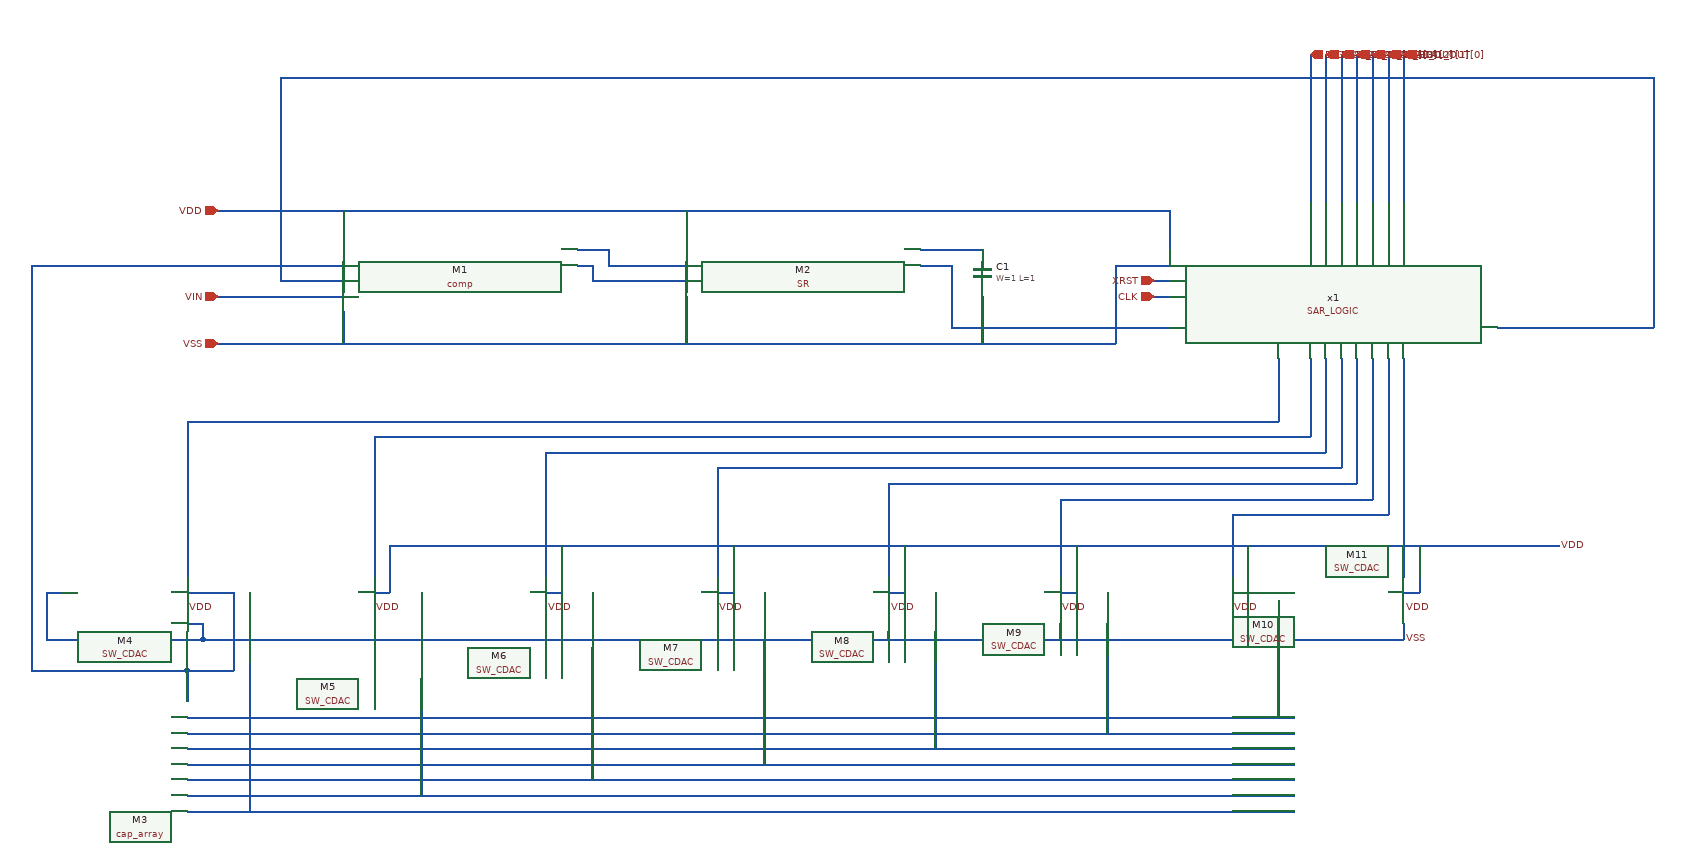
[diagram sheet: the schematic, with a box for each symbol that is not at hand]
v {xschem version=3.4.8RC file_version=1.3}
G {}
K {}
V {}
S {}
F {}
E {}
N 2480 -820 2760 -820 {
lab=#net1}
N 2740 -860 2760 -860 {
lab=CLK}
N 2740 -880 2760 -880 {
lab=XRST}
N 3060 -780 3060 -690 {
lab=#net2}
N 3040 -780 3040 -690 {
lab=#net3}
N 3020 -780 3020 -690 {
lab=#net4}
N 3000 -780 3000 -690 {
lab=#net5}
N 2980 -780 2980 -690 {
lab=#net6}
N 2960 -780 2960 -690 {
lab=#net7}
N 2940 -780 2940 -690 {
lab=#net8}
N 2900 -780 2900 -700 {
lab=#net9}
N 3180 -820 3380 -820 {
lab=#net10}
N 2000 -920 2040 -920 {
lab=#net11}
N 2000 -900 2020 -900 {
lab=#net12}
N 1500 -320 2920 -320 {
lab=#net13}
N 1500 -300 2920 -300 {
lab=#net14}
N 1500 -280 2920 -280 {
lab=#net15}
N 1500 -260 2920 -260 {
lab=#net16}
N 1500 -240 2920 -240 {
lab=#net17}
N 1500 -220 2920 -220 {
lab=#net18}
N 1500 -200 2920 -200 {
lab=#net19}
N 1740 -680 2940 -680 {
lab=#net8}
N 1740 -680 1740 -500 {
lab=#net8}
N 1960 -660 1960 -500 {
lab=#net7}
N 1960 -660 2960 -660 {
lab=#net7}
N 2180 -640 2980 -640 {
lab=#net6}
N 2180 -640 2180 -500 {
lab=#net6}
N 2400 -620 2400 -500 {
lab=#net5}
N 2400 -620 3000 -620 {
lab=#net5}
N 2620 -600 3020 -600 {
lab=#net4}
N 2620 -600 2620 -500 {
lab=#net4}
N 2840 -580 2840 -500 {
lab=#net3}
N 3060 -690 3060 -500 {
lab=#net2}
N 1500 -700 2900 -700 {
lab=#net9}
N 1500 -700 1500 -500 {
lab=#net9}
N 1320 -480 1340 -480 {
lab=VSS}
N 1320 -480 1320 -420 {
lab=VSS}
N 1320 -420 1520 -420 {
lab=VSS}
N 1520 -440 1520 -420 {
lab=VSS}
N 1500 -440 1520 -440 {
lab=VSS}
N 1500 -380 1500 -340 {
lab=#net20}
N 1300 -380 1500 -380 {
lab=#net20}
N 1300 -900 1300 -380 {
lab=#net20}
N 1300 -900 1700 -900 {
lab=#net20}
N 1500 -480 1560 -480 {
lab=#net20}
N 1560 -480 1560 -380 {
lab=#net20}
N 1500 -380 1560 -380 {
lab=#net20}
N 2840 -580 3040 -580 {
lab=#net3}
N 1620 -880 1700 -880 {
lab=#net10}
N 1620 -1140 1620 -880 {
lab=#net10}
N 1620 -1140 3380 -1140 {
lab=#net10}
N 3380 -1140 3380 -820 {
lab=#net10}
N 2440 -900 2480 -900 {
lab=#net1}
N 2480 -900 2480 -820 {
lab=#net1}
N 2440 -920 2520 -920 {
lab=#net21}
N 1760 -540 3260 -540 {
lab=VDD}
N 1740 -480 1760 -480 {
lab=VDD}
N 1760 -540 1760 -480 {
lab=VDD}
N 1960 -480 1980 -480 {
lab=VDD}
N 1980 -540 1980 -480 {
lab=VDD}
N 2180 -480 2200 -480 {
lab=VDD}
N 2200 -540 2200 -480 {
lab=VDD}
N 2400 -480 2420 -480 {
lab=VDD}
N 2420 -540 2420 -480 {
lab=VDD}
N 2620 -480 2640 -480 {
lab=VDD}
N 2640 -540 2640 -480 {
lab=VDD}
N 2840 -480 2860 -480 {
lab=VDD}
N 2860 -540 2860 -480 {
lab=VDD}
N 3060 -480 3080 -480 {
lab=VDD}
N 3080 -540 3080 -480 {
lab=VDD}
N 2040 -920 2040 -900 {
lab=#net11}
N 2940 -690 2940 -680 {
lab=#net8}
N 2960 -690 2960 -660 {
lab=#net7}
N 2980 -690 2980 -640 {
lab=#net6}
N 3000 -690 3000 -620 {
lab=#net5}
N 3020 -690 3020 -600 {
lab=#net4}
N 3040 -690 3040 -580 {
lab=#net3}
N 2020 -480 2020 -240 {
lab=#net17}
N 1800 -480 1800 -220 {
lab=#net18}
N 1580 -480 1580 -200 {
lab=#net19}
N 2940 -1120 2940 -980 {
lab=DIGITAL_OUT[5]}
N 2960 -1120 2960 -980 {
lab=DIGITAL_OUT[4]}
N 2980 -1120 2980 -980 {
lab=DIGITAL_OUT[3]}
N 3000 -1120 3000 -980 {
lab=DIGITAL_OUT[2]}
N 3020 -1120 3020 -980 {
lab=DIGITAL_OUT[1]}
N 3040 -1120 3040 -980 {
lab=DIGITAL_OUT[0]}
N 3060 -1120 3060 -980 {
lab=EOC}
N 2020 -900 2020 -880 {
lab=#net12}
N 2020 -880 2140 -880 {
lab=#net12}
N 2040 -900 2140 -900 {
lab=#net11}
N 1680 -970 2760 -970 {lab=VDD}
N 2760 -970 2760 -920 {lab=VDD}
N 2140 -970 2140 -920 {lab=VDD}
N 1700 -970 1700 -920 {lab=VDD}
N 1690 -800 2690 -800 {lab=VSS}
N 2690 -900 2690 -800 {lab=VSS}
N 2690 -900 2760 -900 {lab=VSS}
N 2520 -860 2520 -800 {lab=VSS}
N 2140 -860 2140 -800 {lab=VSS}
N 1700 -840 1700 -800 {lab=VSS}
N 1520 -420 3060 -420 {lab=VSS}
N 3060 -440 3060 -420 {lab=VSS}
N 1740 -440 1740 -420 {lab=VSS}
N 1960 -440 1960 -420 {lab=VSS}
N 2180 -440 2180 -420 {lab=VSS}
N 2400 -440 2400 -420 {lab=VSS}
N 2620 -440 2620 -420 {lab=VSS}
N 1540 -970 1680 -970 {lab=VDD}
N 1590 -860 1700 -860 {lab=VIN}
N 2940 -1170 2940 -1120 {lab=DIGITAL_OUT[5]}
N 2960 -1170 2960 -1120 {lab=DIGITAL_OUT[4]}
N 2980 -1170 2980 -1120 {lab=DIGITAL_OUT[3]}
N 3000 -1170 3000 -1120 {lab=DIGITAL_OUT[2]}
N 3020 -1170 3020 -1120 {lab=DIGITAL_OUT[1]}
N 3040 -1170 3040 -1120 {lab=DIGITAL_OUT[0]}
N 3060 -1170 3060 -1120 {lab=EOC}
N 1540 -860 1590 -860 {lab=VIN}
N 1540 -800 1690 -800 {lab=VSS}
N 2240 -480 2240 -260 {lab=#net16}
N 2460 -480 2460 -280 {lab=#net15}
N 2680 -480 2680 -300 {lab=#net14}
N 2900 -470 2900 -320 {lab=#net13}
C {devices/lab_pin.sym} 1500 -460 2 0 {name=p1 sig_type=std_logic lab=VDD}
C {devices/lab_pin.sym} 1740 -460 2 0 {name=p3 sig_type=std_logic lab=VDD}
C {devices/lab_pin.sym} 1960 -460 2 0 {name=p4 sig_type=std_logic lab=VDD}
C {devices/lab_pin.sym} 2180 -460 2 0 {name=p6 sig_type=std_logic lab=VDD}
C {devices/lab_pin.sym} 2400 -460 2 0 {name=p8 sig_type=std_logic lab=VDD}
C {devices/lab_pin.sym} 2620 -460 2 0 {name=p22 sig_type=std_logic lab=VDD}
C {devices/lab_pin.sym} 2840 -460 2 0 {name=p23 sig_type=std_logic lab=VDD}
C {devices/lab_pin.sym} 3060 -460 2 0 {name=p24 sig_type=std_logic lab=VDD}
C {SR.sym} 2290 -890 0 0 {name=M2
spiceprefix=X
}
C {SAR_LOGIC.sym} 2970 -870 0 0 {name=x1 prefix=SAR_LOGIC}
C {cap_array.sym} 1350 -270 0 0 {name=M3
spiceprefix=X}
C {SW_CDAC.sym} 1500 -500 0 1 {name=M4
spiceprefix=X}
C {SW_CDAC.sym} 1740 -500 0 1 {name=M5
spiceprefix=X}
C {SW_CDAC.sym} 1960 -500 0 1 {name=M6
spiceprefix=X}
C {SW_CDAC.sym} 2180 -500 0 1 {name=M7
spiceprefix=X}
C {SW_CDAC.sym} 2400 -500 0 1 {name=M8
spiceprefix=X}
C {SW_CDAC.sym} 2620 -500 0 1 {name=M9
spiceprefix=X}
C {SW_CDAC.sym} 2840 -500 0 1 {name=M10
spiceprefix=X}
C {SW_CDAC.sym} 3060 -500 0 1 {name=M11
spiceprefix=X}
C {devices/ipin.sym} 1540 -970 0 0 {name=p2 lab=VDD}
C {devices/ipin.sym} 1540 -800 0 0 {name=p9 lab=VSS}
C {devices/lab_wire.sym} 3060 -420 2 0 {name=p10 sig_type=std_logic lab=VSS}
C {comp.sym} 1850 -880 0 0 {name=M1
spiceprefix=X}
C {devices/lab_pin.sym} 3260 -540 2 0 {name=p11 sig_type=std_logic lab=VDD}
C {devices/ipin.sym} 1540 -860 0 0 {name=p12 lab=VIN}
C {devices/ipin.sym} 2740 -860 0 0 {name=p13 lab=CLK}
C {devices/ipin.sym} 2740 -880 0 0 {name=p5 lab=XRST}
C {devices/opin.sym} 2940 -1170 3 0 {name=p7 lab=DIGITAL_OUT[5]}
C {devices/opin.sym} 2960 -1170 3 0 {name=p14 lab=DIGITAL_OUT[4]}
C {devices/opin.sym} 2980 -1170 3 0 {name=p15 lab=DIGITAL_OUT[3]}
C {devices/opin.sym} 3000 -1170 3 0 {name=p16 lab=DIGITAL_OUT[2]}
C {devices/opin.sym} 3020 -1170 3 0 {name=p19 lab=DIGITAL_OUT[1]}
C {devices/opin.sym} 3040 -1170 3 0 {name=p20 lab=DIGITAL_OUT[0]}
C {devices/opin.sym} 3060 -1170 3 0 {name=p25 lab=EOC}
C {sky130_fd_pr/cap_mim_m3_1.sym} 2520 -890 0 0 {name=C1 model=cap_mim_m3_1 W=1 L=1 MF=1 spiceprefix=X}
